VERSION 5.7 ;
  NOWIREEXTENSIONATPIN ON ;
  DIVIDERCHAR "/" ;
  BUSBITCHARS "[]" ;
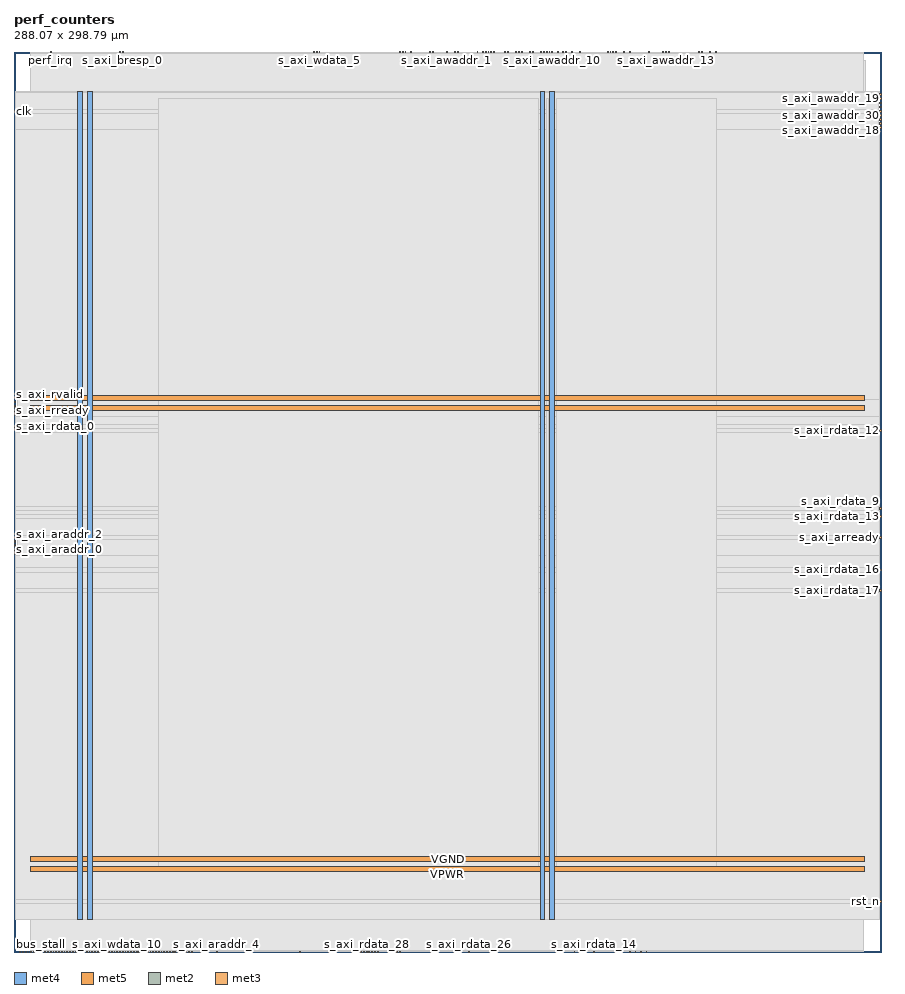
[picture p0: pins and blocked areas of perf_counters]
MACRO perf_counters
  CLASS BLOCK ;
  FOREIGN perf_counters ;
  ORIGIN 0.000 0.000 ;
  SIZE 288.070 BY 298.790 ;
  PIN VGND
    DIRECTION INOUT ;
    USE GROUND ;
    PORT
      LAYER met4 ;
        RECT 24.340 10.640 25.940 285.840 ;
    END
    PORT
      LAYER met4 ;
        RECT 177.940 10.640 179.540 285.840 ;
    END
    PORT
      LAYER met5 ;
        RECT 5.520 30.030 282.440 31.630 ;
    END
    PORT
      LAYER met5 ;
        RECT 5.520 183.210 282.440 184.810 ;
    END
  END VGND
  PIN VPWR
    DIRECTION INOUT ;
    USE POWER ;
    PORT
      LAYER met4 ;
        RECT 21.040 10.640 22.640 285.840 ;
    END
    PORT
      LAYER met4 ;
        RECT 174.640 10.640 176.240 285.840 ;
    END
    PORT
      LAYER met5 ;
        RECT 5.520 26.730 282.440 28.330 ;
    END
    PORT
      LAYER met5 ;
        RECT 5.520 179.910 282.440 181.510 ;
    END
  END VPWR
  PIN accel_busy
    DIRECTION INPUT ;
    USE SIGNAL ;
    PORT
      LAYER met2 ;
        RECT 1.930 0.000 2.210 0.280 ;
    END
  END accel_busy
  PIN bus_stall
    DIRECTION INPUT ;
    USE SIGNAL ;
    PORT
      LAYER met2 ;
        RECT 2.850 0.000 3.130 0.280 ;
    END
  END bus_stall
  PIN cache_hit
    DIRECTION INPUT ;
    USE SIGNAL ;
    PORT
      LAYER met2 ;
        RECT 3.770 0.000 4.050 0.280 ;
    END
  END cache_hit
  PIN cache_miss
    DIRECTION INPUT ;
    USE SIGNAL ;
    PORT
      LAYER met2 ;
        RECT 4.690 0.000 4.970 0.280 ;
    END
  END cache_miss
  PIN clk
    DIRECTION INPUT ;
    USE SIGNAL ;
    ANTENNAGATEAREA 1.286700 ;
    ANTENNADIFFAREA 0.434700 ;
    PORT
      LAYER met3 ;
        RECT 0.000 278.840 0.600 279.440 ;
    END
  END clk
  PIN dma_active
    DIRECTION INPUT ;
    USE SIGNAL ;
    PORT
      LAYER met2 ;
        RECT 5.610 0.000 5.890 0.280 ;
    END
  END dma_active
  PIN dmem_req
    DIRECTION INPUT ;
    USE SIGNAL ;
    PORT
      LAYER met2 ;
        RECT 6.530 0.000 6.810 0.280 ;
    END
  END dmem_req
  PIN dmem_wr
    DIRECTION INPUT ;
    USE SIGNAL ;
    PORT
      LAYER met2 ;
        RECT 7.450 0.000 7.730 0.280 ;
    END
  END dmem_wr
  PIN imem_req
    DIRECTION INPUT ;
    USE SIGNAL ;
    PORT
      LAYER met2 ;
        RECT 8.370 0.000 8.650 0.280 ;
    END
  END imem_req
  PIN irq_taken
    DIRECTION INPUT ;
    USE SIGNAL ;
    PORT
      LAYER met2 ;
        RECT 9.290 0.000 9.570 0.280 ;
    END
  END irq_taken
  PIN perf_irq
    DIRECTION OUTPUT ;
    USE SIGNAL ;
    ANTENNAGATEAREA 0.434700 ;
    ANTENNADIFFAREA 0.434700 ;
    PORT
      LAYER met2 ;
        RECT 12.050 298.510 12.330 298.790 ;
    END
  END perf_irq
  PIN rst_n
    DIRECTION INPUT ;
    USE SIGNAL ;
    ANTENNAGATEAREA 0.647700 ;
    ANTENNADIFFAREA 0.434700 ;
    PORT
      LAYER met3 ;
        RECT 287.470 16.360 288.070 16.960 ;
    END
  END rst_n
  PIN s_axi_araddr_0
    DIRECTION INPUT ;
    USE SIGNAL ;
    ANTENNAGATEAREA 0.647700 ;
    ANTENNADIFFAREA 0.434700 ;
    PORT
      LAYER met3 ;
        RECT 0.000 133.320 0.600 133.920 ;
    END
  END s_axi_araddr_0
  PIN s_axi_araddr_1
    DIRECTION INPUT ;
    USE SIGNAL ;
    ANTENNAGATEAREA 0.647700 ;
    ANTENNADIFFAREA 0.434700 ;
    PORT
      LAYER met3 ;
        RECT 0.000 134.680 0.600 135.280 ;
    END
  END s_axi_araddr_1
  PIN s_axi_araddr_10
    DIRECTION INPUT ;
    USE SIGNAL ;
    PORT
      LAYER met2 ;
        RECT 10.210 0.000 10.490 0.280 ;
    END
  END s_axi_araddr_10
  PIN s_axi_araddr_11
    DIRECTION INPUT ;
    USE SIGNAL ;
    PORT
      LAYER met2 ;
        RECT 11.130 0.000 11.410 0.280 ;
    END
  END s_axi_araddr_11
  PIN s_axi_araddr_12
    DIRECTION INPUT ;
    USE SIGNAL ;
    PORT
      LAYER met2 ;
        RECT 12.050 0.000 12.330 0.280 ;
    END
  END s_axi_araddr_12
  PIN s_axi_araddr_13
    DIRECTION INPUT ;
    USE SIGNAL ;
    PORT
      LAYER met2 ;
        RECT 12.970 0.000 13.250 0.280 ;
    END
  END s_axi_araddr_13
  PIN s_axi_araddr_14
    DIRECTION INPUT ;
    USE SIGNAL ;
    PORT
      LAYER met2 ;
        RECT 13.890 0.000 14.170 0.280 ;
    END
  END s_axi_araddr_14
  PIN s_axi_araddr_15
    DIRECTION INPUT ;
    USE SIGNAL ;
    PORT
      LAYER met2 ;
        RECT 14.810 0.000 15.090 0.280 ;
    END
  END s_axi_araddr_15
  PIN s_axi_araddr_16
    DIRECTION INPUT ;
    USE SIGNAL ;
    PORT
      LAYER met2 ;
        RECT 15.730 0.000 16.010 0.280 ;
    END
  END s_axi_araddr_16
  PIN s_axi_araddr_17
    DIRECTION INPUT ;
    USE SIGNAL ;
    PORT
      LAYER met2 ;
        RECT 16.650 0.000 16.930 0.280 ;
    END
  END s_axi_araddr_17
  PIN s_axi_araddr_18
    DIRECTION INPUT ;
    USE SIGNAL ;
    PORT
      LAYER met2 ;
        RECT 17.570 0.000 17.850 0.280 ;
    END
  END s_axi_araddr_18
  PIN s_axi_araddr_19
    DIRECTION INPUT ;
    USE SIGNAL ;
    PORT
      LAYER met2 ;
        RECT 18.490 0.000 18.770 0.280 ;
    END
  END s_axi_araddr_19
  PIN s_axi_araddr_2
    DIRECTION INPUT ;
    USE SIGNAL ;
    ANTENNAGATEAREA 0.647700 ;
    ANTENNADIFFAREA 0.434700 ;
    PORT
      LAYER met3 ;
        RECT 0.000 136.040 0.600 136.640 ;
    END
  END s_axi_araddr_2
  PIN s_axi_araddr_20
    DIRECTION INPUT ;
    USE SIGNAL ;
    PORT
      LAYER met2 ;
        RECT 19.410 0.000 19.690 0.280 ;
    END
  END s_axi_araddr_20
  PIN s_axi_araddr_21
    DIRECTION INPUT ;
    USE SIGNAL ;
    PORT
      LAYER met2 ;
        RECT 20.330 0.000 20.610 0.280 ;
    END
  END s_axi_araddr_21
  PIN s_axi_araddr_22
    DIRECTION INPUT ;
    USE SIGNAL ;
    PORT
      LAYER met2 ;
        RECT 21.250 0.000 21.530 0.280 ;
    END
  END s_axi_araddr_22
  PIN s_axi_araddr_23
    DIRECTION INPUT ;
    USE SIGNAL ;
    PORT
      LAYER met2 ;
        RECT 22.170 0.000 22.450 0.280 ;
    END
  END s_axi_araddr_23
  PIN s_axi_araddr_24
    DIRECTION INPUT ;
    USE SIGNAL ;
    PORT
      LAYER met2 ;
        RECT 23.090 0.000 23.370 0.280 ;
    END
  END s_axi_araddr_24
  PIN s_axi_araddr_25
    DIRECTION INPUT ;
    USE SIGNAL ;
    PORT
      LAYER met2 ;
        RECT 24.010 0.000 24.290 0.280 ;
    END
  END s_axi_araddr_25
  PIN s_axi_araddr_26
    DIRECTION INPUT ;
    USE SIGNAL ;
    PORT
      LAYER met2 ;
        RECT 24.930 0.000 25.210 0.280 ;
    END
  END s_axi_araddr_26
  PIN s_axi_araddr_27
    DIRECTION INPUT ;
    USE SIGNAL ;
    PORT
      LAYER met2 ;
        RECT 25.850 0.000 26.130 0.280 ;
    END
  END s_axi_araddr_27
  PIN s_axi_araddr_28
    DIRECTION INPUT ;
    USE SIGNAL ;
    PORT
      LAYER met2 ;
        RECT 26.770 0.000 27.050 0.280 ;
    END
  END s_axi_araddr_28
  PIN s_axi_araddr_29
    DIRECTION INPUT ;
    USE SIGNAL ;
    PORT
      LAYER met2 ;
        RECT 27.690 0.000 27.970 0.280 ;
    END
  END s_axi_araddr_29
  PIN s_axi_araddr_3
    DIRECTION INPUT ;
    USE SIGNAL ;
    ANTENNAGATEAREA 0.647700 ;
    ANTENNADIFFAREA 0.434700 ;
    PORT
      LAYER met3 ;
        RECT 0.000 131.960 0.600 132.560 ;
    END
  END s_axi_araddr_3
  PIN s_axi_araddr_30
    DIRECTION INPUT ;
    USE SIGNAL ;
    PORT
      LAYER met2 ;
        RECT 28.610 0.000 28.890 0.280 ;
    END
  END s_axi_araddr_30
  PIN s_axi_araddr_31
    DIRECTION INPUT ;
    USE SIGNAL ;
    PORT
      LAYER met2 ;
        RECT 29.530 0.000 29.810 0.280 ;
    END
  END s_axi_araddr_31
  PIN s_axi_araddr_4
    DIRECTION INPUT ;
    USE SIGNAL ;
    ANTENNAGATEAREA 0.631200 ;
    ANTENNADIFFAREA 0.434700 ;
    PORT
      LAYER met2 ;
        RECT 67.250 0.000 67.530 0.280 ;
    END
  END s_axi_araddr_4
  PIN s_axi_araddr_5
    DIRECTION INPUT ;
    USE SIGNAL ;
    PORT
      LAYER met2 ;
        RECT 30.450 0.000 30.730 0.280 ;
    END
  END s_axi_araddr_5
  PIN s_axi_araddr_6
    DIRECTION INPUT ;
    USE SIGNAL ;
    PORT
      LAYER met2 ;
        RECT 31.370 0.000 31.650 0.280 ;
    END
  END s_axi_araddr_6
  PIN s_axi_araddr_7
    DIRECTION INPUT ;
    USE SIGNAL ;
    ANTENNAGATEAREA 0.647700 ;
    ANTENNADIFFAREA 0.434700 ;
    PORT
      LAYER met2 ;
        RECT 94.850 0.000 95.130 0.280 ;
    END
  END s_axi_araddr_7
  PIN s_axi_araddr_8
    DIRECTION INPUT ;
    USE SIGNAL ;
    PORT
      LAYER met2 ;
        RECT 32.290 0.000 32.570 0.280 ;
    END
  END s_axi_araddr_8
  PIN s_axi_araddr_9
    DIRECTION INPUT ;
    USE SIGNAL ;
    PORT
      LAYER met2 ;
        RECT 33.210 0.000 33.490 0.280 ;
    END
  END s_axi_araddr_9
  PIN s_axi_arready
    DIRECTION OUTPUT ;
    USE SIGNAL ;
    ANTENNAGATEAREA 0.434700 ;
    ANTENNADIFFAREA 1.137600 ;
    PORT
      LAYER met3 ;
        RECT 287.470 137.400 288.070 138.000 ;
    END
  END s_axi_arready
  PIN s_axi_arvalid
    DIRECTION INPUT ;
    USE SIGNAL ;
    ANTENNAGATEAREA 0.647700 ;
    ANTENNADIFFAREA 0.434700 ;
    PORT
      LAYER met3 ;
        RECT 0.000 180.920 0.600 181.520 ;
    END
  END s_axi_arvalid
  PIN s_axi_awaddr_0
    DIRECTION INPUT ;
    USE SIGNAL ;
    ANTENNAGATEAREA 0.647700 ;
    ANTENNADIFFAREA 0.434700 ;
    PORT
      LAYER met2 ;
        RECT 129.810 298.510 130.090 298.790 ;
    END
  END s_axi_awaddr_0
  PIN s_axi_awaddr_1
    DIRECTION INPUT ;
    USE SIGNAL ;
    ANTENNAGATEAREA 0.647700 ;
    ANTENNADIFFAREA 0.434700 ;
    PORT
      LAYER met2 ;
        RECT 143.610 298.510 143.890 298.790 ;
    END
  END s_axi_awaddr_1
  PIN s_axi_awaddr_10
    DIRECTION INPUT ;
    USE SIGNAL ;
    ANTENNAGATEAREA 0.647700 ;
    ANTENNADIFFAREA 0.434700 ;
    PORT
      LAYER met2 ;
        RECT 178.570 298.510 178.850 298.790 ;
    END
  END s_axi_awaddr_10
  PIN s_axi_awaddr_11
    DIRECTION INPUT ;
    USE SIGNAL ;
    ANTENNAGATEAREA 0.647700 ;
    ANTENNADIFFAREA 0.434700 ;
    PORT
      LAYER met2 ;
        RECT 187.770 298.510 188.050 298.790 ;
    END
  END s_axi_awaddr_11
  PIN s_axi_awaddr_12
    DIRECTION INPUT ;
    USE SIGNAL ;
    ANTENNAGATEAREA 0.647700 ;
    ANTENNADIFFAREA 0.434700 ;
    PORT
      LAYER met3 ;
        RECT 287.470 284.280 288.070 284.880 ;
    END
  END s_axi_awaddr_12
  PIN s_axi_awaddr_13
    DIRECTION INPUT ;
    USE SIGNAL ;
    ANTENNAGATEAREA 0.647700 ;
    ANTENNADIFFAREA 0.434700 ;
    PORT
      LAYER met2 ;
        RECT 216.290 298.510 216.570 298.790 ;
    END
  END s_axi_awaddr_13
  PIN s_axi_awaddr_14
    DIRECTION INPUT ;
    USE SIGNAL ;
    ANTENNAGATEAREA 0.647700 ;
    ANTENNADIFFAREA 0.434700 ;
    PORT
      LAYER met2 ;
        RECT 210.770 298.510 211.050 298.790 ;
    END
  END s_axi_awaddr_14
  PIN s_axi_awaddr_15
    DIRECTION INPUT ;
    USE SIGNAL ;
    ANTENNAGATEAREA 0.647700 ;
    ANTENNADIFFAREA 0.434700 ;
    PORT
      LAYER met3 ;
        RECT 287.470 278.840 288.070 279.440 ;
    END
  END s_axi_awaddr_15
  PIN s_axi_awaddr_16
    DIRECTION INPUT ;
    USE SIGNAL ;
    ANTENNAGATEAREA 0.647700 ;
    ANTENNADIFFAREA 0.434700 ;
    PORT
      LAYER met2 ;
        RECT 227.330 298.510 227.610 298.790 ;
    END
  END s_axi_awaddr_16
  PIN s_axi_awaddr_17
    DIRECTION INPUT ;
    USE SIGNAL ;
    ANTENNAGATEAREA 0.647700 ;
    ANTENNADIFFAREA 0.434700 ;
    PORT
      LAYER met2 ;
        RECT 202.490 298.510 202.770 298.790 ;
    END
  END s_axi_awaddr_17
  PIN s_axi_awaddr_18
    DIRECTION INPUT ;
    USE SIGNAL ;
    ANTENNAGATEAREA 0.647700 ;
    ANTENNADIFFAREA 0.434700 ;
    PORT
      LAYER met3 ;
        RECT 287.470 274.760 288.070 275.360 ;
    END
  END s_axi_awaddr_18
  PIN s_axi_awaddr_19
    DIRECTION INPUT ;
    USE SIGNAL ;
    ANTENNAGATEAREA 0.647700 ;
    ANTENNADIFFAREA 0.434700 ;
    PORT
      LAYER met3 ;
        RECT 287.470 282.920 288.070 283.520 ;
    END
  END s_axi_awaddr_19
  PIN s_axi_awaddr_2
    DIRECTION INPUT ;
    USE SIGNAL ;
    ANTENNAGATEAREA 0.647700 ;
    ANTENNADIFFAREA 0.434700 ;
    PORT
      LAYER met2 ;
        RECT 147.290 298.510 147.570 298.790 ;
    END
  END s_axi_awaddr_2
  PIN s_axi_awaddr_20
    DIRECTION INPUT ;
    USE SIGNAL ;
    ANTENNAGATEAREA 0.647700 ;
    ANTENNADIFFAREA 0.434700 ;
    PORT
      LAYER met3 ;
        RECT 287.470 276.120 288.070 276.720 ;
    END
  END s_axi_awaddr_20
  PIN s_axi_awaddr_21
    DIRECTION INPUT ;
    USE SIGNAL ;
    ANTENNAGATEAREA 0.647700 ;
    ANTENNADIFFAREA 0.434700 ;
    PORT
      LAYER met2 ;
        RECT 231.010 298.510 231.290 298.790 ;
    END
  END s_axi_awaddr_21
  PIN s_axi_awaddr_22
    DIRECTION INPUT ;
    USE SIGNAL ;
    ANTENNAGATEAREA 0.647700 ;
    ANTENNADIFFAREA 0.434700 ;
    PORT
      LAYER met3 ;
        RECT 287.470 281.560 288.070 282.160 ;
    END
  END s_axi_awaddr_22
  PIN s_axi_awaddr_23
    DIRECTION INPUT ;
    USE SIGNAL ;
    ANTENNAGATEAREA 0.647700 ;
    ANTENNADIFFAREA 0.434700 ;
    PORT
      LAYER met3 ;
        RECT 287.470 280.200 288.070 280.800 ;
    END
  END s_axi_awaddr_23
  PIN s_axi_awaddr_24
    DIRECTION INPUT ;
    USE SIGNAL ;
    ANTENNAGATEAREA 0.647700 ;
    ANTENNADIFFAREA 0.434700 ;
    PORT
      LAYER met2 ;
        RECT 232.850 298.510 233.130 298.790 ;
    END
  END s_axi_awaddr_24
  PIN s_axi_awaddr_25
    DIRECTION INPUT ;
    USE SIGNAL ;
    ANTENNAGATEAREA 0.647700 ;
    ANTENNADIFFAREA 0.434700 ;
    PORT
      LAYER met2 ;
        RECT 215.370 298.510 215.650 298.790 ;
    END
  END s_axi_awaddr_25
  PIN s_axi_awaddr_26
    DIRECTION INPUT ;
    USE SIGNAL ;
    ANTENNAGATEAREA 0.647700 ;
    ANTENNADIFFAREA 0.434700 ;
    PORT
      LAYER met2 ;
        RECT 196.970 298.510 197.250 298.790 ;
    END
  END s_axi_awaddr_26
  PIN s_axi_awaddr_27
    DIRECTION INPUT ;
    USE SIGNAL ;
    ANTENNAGATEAREA 0.647700 ;
    ANTENNADIFFAREA 0.434700 ;
    PORT
      LAYER met2 ;
        RECT 197.890 298.510 198.170 298.790 ;
    END
  END s_axi_awaddr_27
  PIN s_axi_awaddr_28
    DIRECTION INPUT ;
    USE SIGNAL ;
    ANTENNAGATEAREA 0.647700 ;
    ANTENNADIFFAREA 0.434700 ;
    PORT
      LAYER met2 ;
        RECT 217.210 298.510 217.490 298.790 ;
    END
  END s_axi_awaddr_28
  PIN s_axi_awaddr_29
    DIRECTION INPUT ;
    USE SIGNAL ;
    ANTENNAGATEAREA 0.647700 ;
    ANTENNADIFFAREA 0.434700 ;
    PORT
      LAYER met2 ;
        RECT 228.250 298.510 228.530 298.790 ;
    END
  END s_axi_awaddr_29
  PIN s_axi_awaddr_3
    DIRECTION INPUT ;
    USE SIGNAL ;
    ANTENNAGATEAREA 0.647700 ;
    ANTENNADIFFAREA 0.434700 ;
    PORT
      LAYER met2 ;
        RECT 159.250 298.510 159.530 298.790 ;
    END
  END s_axi_awaddr_3
  PIN s_axi_awaddr_30
    DIRECTION INPUT ;
    USE SIGNAL ;
    ANTENNAGATEAREA 0.647700 ;
    ANTENNADIFFAREA 0.434700 ;
    PORT
      LAYER met3 ;
        RECT 287.470 277.480 288.070 278.080 ;
    END
  END s_axi_awaddr_30
  PIN s_axi_awaddr_31
    DIRECTION INPUT ;
    USE SIGNAL ;
    ANTENNAGATEAREA 0.647700 ;
    ANTENNADIFFAREA 0.434700 ;
    PORT
      LAYER met3 ;
        RECT 287.470 273.400 288.070 274.000 ;
    END
  END s_axi_awaddr_31
  PIN s_axi_awaddr_4
    DIRECTION INPUT ;
    USE SIGNAL ;
    ANTENNAGATEAREA 0.647700 ;
    ANTENNADIFFAREA 0.434700 ;
    PORT
      LAYER met2 ;
        RECT 139.010 298.510 139.290 298.790 ;
    END
  END s_axi_awaddr_4
  PIN s_axi_awaddr_5
    DIRECTION INPUT ;
    USE SIGNAL ;
    ANTENNAGATEAREA 0.647700 ;
    ANTENNADIFFAREA 0.434700 ;
    PORT
      LAYER met2 ;
        RECT 157.410 298.510 157.690 298.790 ;
    END
  END s_axi_awaddr_5
  PIN s_axi_awaddr_6
    DIRECTION INPUT ;
    USE SIGNAL ;
    ANTENNAGATEAREA 0.647700 ;
    ANTENNADIFFAREA 0.434700 ;
    PORT
      LAYER met2 ;
        RECT 127.970 298.510 128.250 298.790 ;
    END
  END s_axi_awaddr_6
  PIN s_axi_awaddr_7
    DIRECTION INPUT ;
    USE SIGNAL ;
    ANTENNAGATEAREA 0.647700 ;
    ANTENNADIFFAREA 0.434700 ;
    PORT
      LAYER met2 ;
        RECT 128.890 298.510 129.170 298.790 ;
    END
  END s_axi_awaddr_7
  PIN s_axi_awaddr_8
    DIRECTION INPUT ;
    USE SIGNAL ;
    ANTENNAGATEAREA 0.647700 ;
    ANTENNADIFFAREA 0.434700 ;
    PORT
      LAYER met2 ;
        RECT 185.010 298.510 185.290 298.790 ;
    END
  END s_axi_awaddr_8
  PIN s_axi_awaddr_9
    DIRECTION INPUT ;
    USE SIGNAL ;
    ANTENNAGATEAREA 0.647700 ;
    ANTENNADIFFAREA 0.434700 ;
    PORT
      LAYER met2 ;
        RECT 182.250 298.510 182.530 298.790 ;
    END
  END s_axi_awaddr_9
  PIN s_axi_awready
    DIRECTION OUTPUT ;
    USE SIGNAL ;
    ANTENNAGATEAREA 0.434700 ;
    ANTENNADIFFAREA 1.137600 ;
    PORT
      LAYER met2 ;
        RECT 183.170 298.510 183.450 298.790 ;
    END
  END s_axi_awready
  PIN s_axi_awvalid
    DIRECTION INPUT ;
    USE SIGNAL ;
    ANTENNAGATEAREA 0.647700 ;
    ANTENNADIFFAREA 0.434700 ;
    PORT
      LAYER met2 ;
        RECT 172.130 298.510 172.410 298.790 ;
    END
  END s_axi_awvalid
  PIN s_axi_bready
    DIRECTION INPUT ;
    USE SIGNAL ;
    ANTENNAGATEAREA 0.647700 ;
    ANTENNADIFFAREA 0.434700 ;
    PORT
      LAYER met2 ;
        RECT 162.930 298.510 163.210 298.790 ;
    END
  END s_axi_bready
  PIN s_axi_bresp_0
    DIRECTION OUTPUT ;
    USE SIGNAL ;
    ANTENNAGATEAREA 0.434700 ;
    ANTENNADIFFAREA 1.137600 ;
    PORT
      LAYER met2 ;
        RECT 35.970 298.510 36.250 298.790 ;
    END
  END s_axi_bresp_0
  PIN s_axi_bresp_1
    DIRECTION OUTPUT ;
    USE SIGNAL ;
    ANTENNAGATEAREA 0.434700 ;
    ANTENNADIFFAREA 1.137600 ;
    PORT
      LAYER met2 ;
        RECT 35.050 298.510 35.330 298.790 ;
    END
  END s_axi_bresp_1
  PIN s_axi_bvalid
    DIRECTION OUTPUT ;
    USE SIGNAL ;
    ANTENNAGATEAREA 0.434700 ;
    ANTENNADIFFAREA 1.137600 ;
    PORT
      LAYER met2 ;
        RECT 166.610 298.510 166.890 298.790 ;
    END
  END s_axi_bvalid
  PIN s_axi_rdata_0
    DIRECTION OUTPUT ;
    USE SIGNAL ;
    ANTENNAGATEAREA 0.434700 ;
    ANTENNADIFFAREA 1.137600 ;
    PORT
      LAYER met3 ;
        RECT 0.000 174.120 0.600 174.720 ;
    END
  END s_axi_rdata_0
  PIN s_axi_rdata_1
    DIRECTION OUTPUT ;
    USE SIGNAL ;
    ANTENNAGATEAREA 0.434700 ;
    ANTENNADIFFAREA 1.137600 ;
    PORT
      LAYER met2 ;
        RECT 171.210 298.510 171.490 298.790 ;
    END
  END s_axi_rdata_1
  PIN s_axi_rdata_10
    DIRECTION OUTPUT ;
    USE SIGNAL ;
    ANTENNAGATEAREA 0.434700 ;
    ANTENNADIFFAREA 1.137600 ;
    PORT
      LAYER met2 ;
        RECT 204.330 298.510 204.610 298.790 ;
    END
  END s_axi_rdata_10
  PIN s_axi_rdata_11
    DIRECTION OUTPUT ;
    USE SIGNAL ;
    ANTENNAGATEAREA 0.434700 ;
    ANTENNADIFFAREA 1.137600 ;
    PORT
      LAYER met2 ;
        RECT 198.810 298.510 199.090 298.790 ;
    END
  END s_axi_rdata_11
  PIN s_axi_rdata_12
    DIRECTION OUTPUT ;
    USE SIGNAL ;
    ANTENNAGATEAREA 0.434700 ;
    ANTENNADIFFAREA 1.137600 ;
    PORT
      LAYER met3 ;
        RECT 287.470 172.760 288.070 173.360 ;
    END
  END s_axi_rdata_12
  PIN s_axi_rdata_13
    DIRECTION OUTPUT ;
    USE SIGNAL ;
    ANTENNAGATEAREA 0.434700 ;
    ANTENNADIFFAREA 1.137600 ;
    PORT
      LAYER met3 ;
        RECT 287.470 144.200 288.070 144.800 ;
    END
  END s_axi_rdata_13
  PIN s_axi_rdata_14
    DIRECTION OUTPUT ;
    USE SIGNAL ;
    ANTENNAGATEAREA 0.434700 ;
    ANTENNADIFFAREA 1.137600 ;
    PORT
      LAYER met2 ;
        RECT 192.370 0.000 192.650 0.280 ;
    END
  END s_axi_rdata_14
  PIN s_axi_rdata_15
    DIRECTION OUTPUT ;
    USE SIGNAL ;
    ANTENNAGATEAREA 0.434700 ;
    ANTENNADIFFAREA 1.137600 ;
    PORT
      LAYER met2 ;
        RECT 206.170 0.000 206.450 0.280 ;
    END
  END s_axi_rdata_15
  PIN s_axi_rdata_16
    DIRECTION OUTPUT ;
    USE SIGNAL ;
    ANTENNAGATEAREA 0.434700 ;
    ANTENNADIFFAREA 1.137600 ;
    PORT
      LAYER met3 ;
        RECT 287.470 126.520 288.070 127.120 ;
    END
  END s_axi_rdata_16
  PIN s_axi_rdata_17
    DIRECTION OUTPUT ;
    USE SIGNAL ;
    ANTENNAGATEAREA 0.434700 ;
    ANTENNADIFFAREA 1.137600 ;
    PORT
      LAYER met3 ;
        RECT 287.470 119.720 288.070 120.320 ;
    END
  END s_axi_rdata_17
  PIN s_axi_rdata_18
    DIRECTION OUTPUT ;
    USE SIGNAL ;
    ANTENNAGATEAREA 0.434700 ;
    ANTENNADIFFAREA 1.137600 ;
    PORT
      LAYER met2 ;
        RECT 209.850 0.000 210.130 0.280 ;
    END
  END s_axi_rdata_18
  PIN s_axi_rdata_19
    DIRECTION OUTPUT ;
    USE SIGNAL ;
    ANTENNAGATEAREA 0.434700 ;
    ANTENNADIFFAREA 1.137600 ;
    PORT
      LAYER met2 ;
        RECT 208.010 0.000 208.290 0.280 ;
    END
  END s_axi_rdata_19
  PIN s_axi_rdata_2
    DIRECTION OUTPUT ;
    USE SIGNAL ;
    ANTENNAGATEAREA 0.434700 ;
    ANTENNADIFFAREA 1.137600 ;
    PORT
      LAYER met3 ;
        RECT 0.000 178.200 0.600 178.800 ;
    END
  END s_axi_rdata_2
  PIN s_axi_rdata_20
    DIRECTION OUTPUT ;
    USE SIGNAL ;
    ANTENNAGATEAREA 0.434700 ;
    ANTENNADIFFAREA 1.137600 ;
    PORT
      LAYER met2 ;
        RECT 204.330 0.000 204.610 0.280 ;
    END
  END s_axi_rdata_20
  PIN s_axi_rdata_21
    DIRECTION OUTPUT ;
    USE SIGNAL ;
    ANTENNAGATEAREA 0.434700 ;
    ANTENNADIFFAREA 1.137600 ;
    PORT
      LAYER met2 ;
        RECT 185.930 0.000 186.210 0.280 ;
    END
  END s_axi_rdata_21
  PIN s_axi_rdata_22
    DIRECTION OUTPUT ;
    USE SIGNAL ;
    ANTENNAGATEAREA 0.434700 ;
    ANTENNADIFFAREA 1.137600 ;
    PORT
      LAYER met2 ;
        RECT 127.050 0.000 127.330 0.280 ;
    END
  END s_axi_rdata_22
  PIN s_axi_rdata_23
    DIRECTION OUTPUT ;
    USE SIGNAL ;
    ANTENNAGATEAREA 0.434700 ;
    ANTENNADIFFAREA 1.137600 ;
    PORT
      LAYER met2 ;
        RECT 119.690 0.000 119.970 0.280 ;
    END
  END s_axi_rdata_23
  PIN s_axi_rdata_24
    DIRECTION OUTPUT ;
    USE SIGNAL ;
    ANTENNAGATEAREA 0.434700 ;
    ANTENNADIFFAREA 1.137600 ;
    PORT
      LAYER met2 ;
        RECT 127.970 0.000 128.250 0.280 ;
    END
  END s_axi_rdata_24
  PIN s_axi_rdata_25
    DIRECTION OUTPUT ;
    USE SIGNAL ;
    ANTENNAGATEAREA 0.434700 ;
    ANTENNADIFFAREA 1.137600 ;
    PORT
      LAYER met2 ;
        RECT 115.090 0.000 115.370 0.280 ;
    END
  END s_axi_rdata_25
  PIN s_axi_rdata_26
    DIRECTION OUTPUT ;
    USE SIGNAL ;
    ANTENNAGATEAREA 0.434700 ;
    ANTENNADIFFAREA 1.137600 ;
    PORT
      LAYER met2 ;
        RECT 150.970 0.000 151.250 0.280 ;
    END
  END s_axi_rdata_26
  PIN s_axi_rdata_27
    DIRECTION OUTPUT ;
    USE SIGNAL ;
    ANTENNAGATEAREA 0.434700 ;
    ANTENNADIFFAREA 1.137600 ;
    PORT
      LAYER met2 ;
        RECT 116.010 0.000 116.290 0.280 ;
    END
  END s_axi_rdata_27
  PIN s_axi_rdata_28
    DIRECTION OUTPUT ;
    USE SIGNAL ;
    ANTENNAGATEAREA 0.434700 ;
    ANTENNADIFFAREA 1.137600 ;
    PORT
      LAYER met2 ;
        RECT 116.930 0.000 117.210 0.280 ;
    END
  END s_axi_rdata_28
  PIN s_axi_rdata_29
    DIRECTION OUTPUT ;
    USE SIGNAL ;
    ANTENNAGATEAREA 0.434700 ;
    ANTENNADIFFAREA 1.137600 ;
    PORT
      LAYER met2 ;
        RECT 117.850 0.000 118.130 0.280 ;
    END
  END s_axi_rdata_29
  PIN s_axi_rdata_3
    DIRECTION OUTPUT ;
    USE SIGNAL ;
    ANTENNAGATEAREA 0.434700 ;
    ANTENNADIFFAREA 1.137600 ;
    PORT
      LAYER met2 ;
        RECT 131.650 298.510 131.930 298.790 ;
    END
  END s_axi_rdata_3
  PIN s_axi_rdata_30
    DIRECTION OUTPUT ;
    USE SIGNAL ;
    ANTENNAGATEAREA 0.434700 ;
    ANTENNADIFFAREA 1.137600 ;
    PORT
      LAYER met2 ;
        RECT 118.770 0.000 119.050 0.280 ;
    END
  END s_axi_rdata_30
  PIN s_axi_rdata_31
    DIRECTION OUTPUT ;
    USE SIGNAL ;
    ANTENNAGATEAREA 0.434700 ;
    ANTENNADIFFAREA 1.137600 ;
    PORT
      LAYER met2 ;
        RECT 120.610 0.000 120.890 0.280 ;
    END
  END s_axi_rdata_31
  PIN s_axi_rdata_4
    DIRECTION OUTPUT ;
    USE SIGNAL ;
    ANTENNAGATEAREA 0.434700 ;
    ANTENNADIFFAREA 1.137600 ;
    PORT
      LAYER met2 ;
        RECT 168.450 298.510 168.730 298.790 ;
    END
  END s_axi_rdata_4
  PIN s_axi_rdata_5
    DIRECTION OUTPUT ;
    USE SIGNAL ;
    ANTENNAGATEAREA 0.434700 ;
    ANTENNADIFFAREA 1.137600 ;
    PORT
      LAYER met2 ;
        RECT 163.850 298.510 164.130 298.790 ;
    END
  END s_axi_rdata_5
  PIN s_axi_rdata_6
    DIRECTION OUTPUT ;
    USE SIGNAL ;
    ANTENNAGATEAREA 0.434700 ;
    ANTENNADIFFAREA 1.137600 ;
    PORT
      LAYER met2 ;
        RECT 180.410 298.510 180.690 298.790 ;
    END
  END s_axi_rdata_6
  PIN s_axi_rdata_7
    DIRECTION OUTPUT ;
    USE SIGNAL ;
    ANTENNAGATEAREA 0.434700 ;
    ANTENNADIFFAREA 1.137600 ;
    PORT
      LAYER met2 ;
        RECT 177.650 298.510 177.930 298.790 ;
    END
  END s_axi_rdata_7
  PIN s_axi_rdata_8
    DIRECTION OUTPUT ;
    USE SIGNAL ;
    ANTENNAGATEAREA 0.434700 ;
    ANTENNADIFFAREA 1.137600 ;
    PORT
      LAYER met2 ;
        RECT 199.730 298.510 200.010 298.790 ;
    END
  END s_axi_rdata_8
  PIN s_axi_rdata_9
    DIRECTION OUTPUT ;
    USE SIGNAL ;
    ANTENNAGATEAREA 0.434700 ;
    ANTENNADIFFAREA 1.137600 ;
    PORT
      LAYER met3 ;
        RECT 287.470 146.920 288.070 147.520 ;
    END
  END s_axi_rdata_9
  PIN s_axi_rready
    DIRECTION INPUT ;
    USE SIGNAL ;
    ANTENNAGATEAREA 0.647700 ;
    ANTENNADIFFAREA 0.434700 ;
    PORT
      LAYER met3 ;
        RECT 0.000 179.560 0.600 180.160 ;
    END
  END s_axi_rready
  PIN s_axi_rresp_0
    DIRECTION OUTPUT ;
    USE SIGNAL ;
    ANTENNAGATEAREA 0.434700 ;
    ANTENNADIFFAREA 1.137600 ;
    PORT
      LAYER met2 ;
        RECT 175.810 298.510 176.090 298.790 ;
    END
  END s_axi_rresp_0
  PIN s_axi_rresp_1
    DIRECTION OUTPUT ;
    USE SIGNAL ;
    ANTENNAGATEAREA 0.434700 ;
    ANTENNADIFFAREA 1.137600 ;
    PORT
      LAYER met2 ;
        RECT 174.890 298.510 175.170 298.790 ;
    END
  END s_axi_rresp_1
  PIN s_axi_rvalid
    DIRECTION OUTPUT ;
    USE SIGNAL ;
    ANTENNAGATEAREA 0.434700 ;
    ANTENNADIFFAREA 1.137600 ;
    PORT
      LAYER met3 ;
        RECT 0.000 182.280 0.600 182.880 ;
    END
  END s_axi_rvalid
  PIN s_axi_wdata_0
    DIRECTION INPUT ;
    USE SIGNAL ;
    ANTENNAGATEAREA 0.647700 ;
    ANTENNADIFFAREA 0.434700 ;
    PORT
      LAYER met2 ;
        RECT 155.570 298.510 155.850 298.790 ;
    END
  END s_axi_wdata_0
  PIN s_axi_wdata_1
    DIRECTION INPUT ;
    USE SIGNAL ;
    ANTENNAGATEAREA 0.647700 ;
    ANTENNADIFFAREA 0.434700 ;
    PORT
      LAYER met2 ;
        RECT 158.330 298.510 158.610 298.790 ;
    END
  END s_axi_wdata_1
  PIN s_axi_wdata_10
    DIRECTION INPUT ;
    USE SIGNAL ;
    PORT
      LAYER met2 ;
        RECT 34.130 0.000 34.410 0.280 ;
    END
  END s_axi_wdata_10
  PIN s_axi_wdata_11
    DIRECTION INPUT ;
    USE SIGNAL ;
    PORT
      LAYER met2 ;
        RECT 35.050 0.000 35.330 0.280 ;
    END
  END s_axi_wdata_11
  PIN s_axi_wdata_12
    DIRECTION INPUT ;
    USE SIGNAL ;
    PORT
      LAYER met2 ;
        RECT 35.970 0.000 36.250 0.280 ;
    END
  END s_axi_wdata_12
  PIN s_axi_wdata_13
    DIRECTION INPUT ;
    USE SIGNAL ;
    PORT
      LAYER met2 ;
        RECT 36.890 0.000 37.170 0.280 ;
    END
  END s_axi_wdata_13
  PIN s_axi_wdata_14
    DIRECTION INPUT ;
    USE SIGNAL ;
    PORT
      LAYER met2 ;
        RECT 37.810 0.000 38.090 0.280 ;
    END
  END s_axi_wdata_14
  PIN s_axi_wdata_15
    DIRECTION INPUT ;
    USE SIGNAL ;
    PORT
      LAYER met2 ;
        RECT 38.730 0.000 39.010 0.280 ;
    END
  END s_axi_wdata_15
  PIN s_axi_wdata_16
    DIRECTION INPUT ;
    USE SIGNAL ;
    PORT
      LAYER met2 ;
        RECT 39.650 0.000 39.930 0.280 ;
    END
  END s_axi_wdata_16
  PIN s_axi_wdata_17
    DIRECTION INPUT ;
    USE SIGNAL ;
    PORT
      LAYER met2 ;
        RECT 40.570 0.000 40.850 0.280 ;
    END
  END s_axi_wdata_17
  PIN s_axi_wdata_18
    DIRECTION INPUT ;
    USE SIGNAL ;
    PORT
      LAYER met2 ;
        RECT 41.490 0.000 41.770 0.280 ;
    END
  END s_axi_wdata_18
  PIN s_axi_wdata_19
    DIRECTION INPUT ;
    USE SIGNAL ;
    PORT
      LAYER met2 ;
        RECT 42.410 0.000 42.690 0.280 ;
    END
  END s_axi_wdata_19
  PIN s_axi_wdata_2
    DIRECTION INPUT ;
    USE SIGNAL ;
    ANTENNAGATEAREA 0.647700 ;
    ANTENNADIFFAREA 0.434700 ;
    PORT
      LAYER met2 ;
        RECT 153.730 298.510 154.010 298.790 ;
    END
  END s_axi_wdata_2
  PIN s_axi_wdata_20
    DIRECTION INPUT ;
    USE SIGNAL ;
    PORT
      LAYER met2 ;
        RECT 43.330 0.000 43.610 0.280 ;
    END
  END s_axi_wdata_20
  PIN s_axi_wdata_21
    DIRECTION INPUT ;
    USE SIGNAL ;
    PORT
      LAYER met2 ;
        RECT 44.250 0.000 44.530 0.280 ;
    END
  END s_axi_wdata_21
  PIN s_axi_wdata_22
    DIRECTION INPUT ;
    USE SIGNAL ;
    PORT
      LAYER met2 ;
        RECT 45.170 0.000 45.450 0.280 ;
    END
  END s_axi_wdata_22
  PIN s_axi_wdata_23
    DIRECTION INPUT ;
    USE SIGNAL ;
    PORT
      LAYER met2 ;
        RECT 46.090 0.000 46.370 0.280 ;
    END
  END s_axi_wdata_23
  PIN s_axi_wdata_24
    DIRECTION INPUT ;
    USE SIGNAL ;
    PORT
      LAYER met2 ;
        RECT 47.010 0.000 47.290 0.280 ;
    END
  END s_axi_wdata_24
  PIN s_axi_wdata_25
    DIRECTION INPUT ;
    USE SIGNAL ;
    PORT
      LAYER met2 ;
        RECT 47.930 0.000 48.210 0.280 ;
    END
  END s_axi_wdata_25
  PIN s_axi_wdata_26
    DIRECTION INPUT ;
    USE SIGNAL ;
    PORT
      LAYER met2 ;
        RECT 48.850 0.000 49.130 0.280 ;
    END
  END s_axi_wdata_26
  PIN s_axi_wdata_27
    DIRECTION INPUT ;
    USE SIGNAL ;
    PORT
      LAYER met2 ;
        RECT 49.770 0.000 50.050 0.280 ;
    END
  END s_axi_wdata_27
  PIN s_axi_wdata_28
    DIRECTION INPUT ;
    USE SIGNAL ;
    PORT
      LAYER met2 ;
        RECT 50.690 0.000 50.970 0.280 ;
    END
  END s_axi_wdata_28
  PIN s_axi_wdata_29
    DIRECTION INPUT ;
    USE SIGNAL ;
    PORT
      LAYER met2 ;
        RECT 51.610 0.000 51.890 0.280 ;
    END
  END s_axi_wdata_29
  PIN s_axi_wdata_3
    DIRECTION INPUT ;
    USE SIGNAL ;
    ANTENNAGATEAREA 0.647700 ;
    ANTENNADIFFAREA 0.434700 ;
    PORT
      LAYER met2 ;
        RECT 99.450 298.510 99.730 298.790 ;
    END
  END s_axi_wdata_3
  PIN s_axi_wdata_30
    DIRECTION INPUT ;
    USE SIGNAL ;
    PORT
      LAYER met2 ;
        RECT 52.530 0.000 52.810 0.280 ;
    END
  END s_axi_wdata_30
  PIN s_axi_wdata_31
    DIRECTION INPUT ;
    USE SIGNAL ;
    PORT
      LAYER met2 ;
        RECT 53.450 0.000 53.730 0.280 ;
    END
  END s_axi_wdata_31
  PIN s_axi_wdata_4
    DIRECTION INPUT ;
    USE SIGNAL ;
    ANTENNAGATEAREA 0.647700 ;
    ANTENNADIFFAREA 0.434700 ;
    PORT
      LAYER met2 ;
        RECT 100.370 298.510 100.650 298.790 ;
    END
  END s_axi_wdata_4
  PIN s_axi_wdata_5
    DIRECTION INPUT ;
    USE SIGNAL ;
    ANTENNAGATEAREA 0.647700 ;
    ANTENNADIFFAREA 0.434700 ;
    PORT
      LAYER met2 ;
        RECT 101.290 298.510 101.570 298.790 ;
    END
  END s_axi_wdata_5
  PIN s_axi_wdata_6
    DIRECTION INPUT ;
    USE SIGNAL ;
    ANTENNAGATEAREA 0.647700 ;
    ANTENNADIFFAREA 0.434700 ;
    PORT
      LAYER met2 ;
        RECT 146.370 298.510 146.650 298.790 ;
    END
  END s_axi_wdata_6
  PIN s_axi_wdata_7
    DIRECTION INPUT ;
    USE SIGNAL ;
    ANTENNAGATEAREA 0.647700 ;
    ANTENNADIFFAREA 0.434700 ;
    PORT
      LAYER met2 ;
        RECT 138.090 298.510 138.370 298.790 ;
    END
  END s_axi_wdata_7
  PIN s_axi_wdata_8
    DIRECTION INPUT ;
    USE SIGNAL ;
    PORT
      LAYER met2 ;
        RECT 54.370 0.000 54.650 0.280 ;
    END
  END s_axi_wdata_8
  PIN s_axi_wdata_9
    DIRECTION INPUT ;
    USE SIGNAL ;
    PORT
      LAYER met2 ;
        RECT 55.290 0.000 55.570 0.280 ;
    END
  END s_axi_wdata_9
  PIN s_axi_wready
    DIRECTION OUTPUT ;
    USE SIGNAL ;
    ANTENNAGATEAREA 0.434700 ;
    ANTENNADIFFAREA 1.137600 ;
    PORT
      LAYER met2 ;
        RECT 176.730 298.510 177.010 298.790 ;
    END
  END s_axi_wready
  PIN s_axi_wstrb_0
    DIRECTION INPUT ;
    USE SIGNAL ;
    ANTENNAGATEAREA 0.647700 ;
    ANTENNADIFFAREA 0.434700 ;
    PORT
      LAYER met2 ;
        RECT 156.490 298.510 156.770 298.790 ;
    END
  END s_axi_wstrb_0
  PIN s_axi_wstrb_1
    DIRECTION INPUT ;
    USE SIGNAL ;
    PORT
      LAYER met2 ;
        RECT 56.210 0.000 56.490 0.280 ;
    END
  END s_axi_wstrb_1
  PIN s_axi_wstrb_2
    DIRECTION INPUT ;
    USE SIGNAL ;
    PORT
      LAYER met2 ;
        RECT 57.130 0.000 57.410 0.280 ;
    END
  END s_axi_wstrb_2
  PIN s_axi_wstrb_3
    DIRECTION INPUT ;
    USE SIGNAL ;
    PORT
      LAYER met2 ;
        RECT 58.050 0.000 58.330 0.280 ;
    END
  END s_axi_wstrb_3
  PIN s_axi_wvalid
    DIRECTION INPUT ;
    USE SIGNAL ;
    ANTENNAGATEAREA 0.647700 ;
    ANTENNADIFFAREA 0.434700 ;
    PORT
      LAYER met2 ;
        RECT 167.530 298.510 167.810 298.790 ;
    END
  END s_axi_wvalid
  PIN sleep_mode
    DIRECTION INPUT ;
    USE SIGNAL ;
    PORT
      LAYER met2 ;
        RECT 58.970 0.000 59.250 0.280 ;
    END
  END sleep_mode
  OBS
      LAYER nwell ;
        RECT 5.330 10.795 282.630 285.790 ;
      LAYER li1 ;
        RECT 5.520 10.795 282.440 285.685 ;
      LAYER met1 ;
        RECT 5.520 10.640 282.740 296.100 ;
      LAYER met2 ;
        RECT 5.610 298.230 11.770 298.510 ;
        RECT 12.610 298.230 34.770 298.510 ;
        RECT 35.610 298.230 35.690 298.510 ;
        RECT 36.530 298.230 99.170 298.510 ;
        RECT 100.010 298.230 100.090 298.510 ;
        RECT 100.930 298.230 101.010 298.510 ;
        RECT 101.850 298.230 127.690 298.510 ;
        RECT 128.530 298.230 128.610 298.510 ;
        RECT 129.450 298.230 129.530 298.510 ;
        RECT 130.370 298.230 131.370 298.510 ;
        RECT 132.210 298.230 137.810 298.510 ;
        RECT 138.650 298.230 138.730 298.510 ;
        RECT 139.570 298.230 143.330 298.510 ;
        RECT 144.170 298.230 146.090 298.510 ;
        RECT 146.930 298.230 147.010 298.510 ;
        RECT 147.850 298.230 153.450 298.510 ;
        RECT 154.290 298.230 155.290 298.510 ;
        RECT 156.130 298.230 156.210 298.510 ;
        RECT 157.050 298.230 157.130 298.510 ;
        RECT 157.970 298.230 158.050 298.510 ;
        RECT 158.890 298.230 158.970 298.510 ;
        RECT 159.810 298.230 162.650 298.510 ;
        RECT 163.490 298.230 163.570 298.510 ;
        RECT 164.410 298.230 166.330 298.510 ;
        RECT 167.170 298.230 167.250 298.510 ;
        RECT 168.090 298.230 168.170 298.510 ;
        RECT 169.010 298.230 170.930 298.510 ;
        RECT 171.770 298.230 171.850 298.510 ;
        RECT 172.690 298.230 174.610 298.510 ;
        RECT 175.450 298.230 175.530 298.510 ;
        RECT 176.370 298.230 176.450 298.510 ;
        RECT 177.290 298.230 177.370 298.510 ;
        RECT 178.210 298.230 178.290 298.510 ;
        RECT 179.130 298.230 180.130 298.510 ;
        RECT 180.970 298.230 181.970 298.510 ;
        RECT 182.810 298.230 182.890 298.510 ;
        RECT 183.730 298.230 184.730 298.510 ;
        RECT 185.570 298.230 187.490 298.510 ;
        RECT 188.330 298.230 196.690 298.510 ;
        RECT 197.530 298.230 197.610 298.510 ;
        RECT 198.450 298.230 198.530 298.510 ;
        RECT 199.370 298.230 199.450 298.510 ;
        RECT 200.290 298.230 202.210 298.510 ;
        RECT 203.050 298.230 204.050 298.510 ;
        RECT 204.890 298.230 210.490 298.510 ;
        RECT 211.330 298.230 215.090 298.510 ;
        RECT 215.930 298.230 216.010 298.510 ;
        RECT 216.850 298.230 216.930 298.510 ;
        RECT 217.770 298.230 227.050 298.510 ;
        RECT 227.890 298.230 227.970 298.510 ;
        RECT 228.810 298.230 230.730 298.510 ;
        RECT 231.570 298.230 232.570 298.510 ;
        RECT 233.410 298.230 281.890 298.510 ;
        RECT 5.610 0.560 281.890 298.230 ;
        RECT 6.170 0.280 6.250 0.560 ;
        RECT 7.090 0.280 7.170 0.560 ;
        RECT 8.010 0.280 8.090 0.560 ;
        RECT 8.930 0.280 9.010 0.560 ;
        RECT 9.850 0.280 9.930 0.560 ;
        RECT 10.770 0.280 10.850 0.560 ;
        RECT 11.690 0.280 11.770 0.560 ;
        RECT 12.610 0.280 12.690 0.560 ;
        RECT 13.530 0.280 13.610 0.560 ;
        RECT 14.450 0.280 14.530 0.560 ;
        RECT 15.370 0.280 15.450 0.560 ;
        RECT 16.290 0.280 16.370 0.560 ;
        RECT 17.210 0.280 17.290 0.560 ;
        RECT 18.130 0.280 18.210 0.560 ;
        RECT 19.050 0.280 19.130 0.560 ;
        RECT 19.970 0.280 20.050 0.560 ;
        RECT 20.890 0.280 20.970 0.560 ;
        RECT 21.810 0.280 21.890 0.560 ;
        RECT 22.730 0.280 22.810 0.560 ;
        RECT 23.650 0.280 23.730 0.560 ;
        RECT 24.570 0.280 24.650 0.560 ;
        RECT 25.490 0.280 25.570 0.560 ;
        RECT 26.410 0.280 26.490 0.560 ;
        RECT 27.330 0.280 27.410 0.560 ;
        RECT 28.250 0.280 28.330 0.560 ;
        RECT 29.170 0.280 29.250 0.560 ;
        RECT 30.090 0.280 30.170 0.560 ;
        RECT 31.010 0.280 31.090 0.560 ;
        RECT 31.930 0.280 32.010 0.560 ;
        RECT 32.850 0.280 32.930 0.560 ;
        RECT 33.770 0.280 33.850 0.560 ;
        RECT 34.690 0.280 34.770 0.560 ;
        RECT 35.610 0.280 35.690 0.560 ;
        RECT 36.530 0.280 36.610 0.560 ;
        RECT 37.450 0.280 37.530 0.560 ;
        RECT 38.370 0.280 38.450 0.560 ;
        RECT 39.290 0.280 39.370 0.560 ;
        RECT 40.210 0.280 40.290 0.560 ;
        RECT 41.130 0.280 41.210 0.560 ;
        RECT 42.050 0.280 42.130 0.560 ;
        RECT 42.970 0.280 43.050 0.560 ;
        RECT 43.890 0.280 43.970 0.560 ;
        RECT 44.810 0.280 44.890 0.560 ;
        RECT 45.730 0.280 45.810 0.560 ;
        RECT 46.650 0.280 46.730 0.560 ;
        RECT 47.570 0.280 47.650 0.560 ;
        RECT 48.490 0.280 48.570 0.560 ;
        RECT 49.410 0.280 49.490 0.560 ;
        RECT 50.330 0.280 50.410 0.560 ;
        RECT 51.250 0.280 51.330 0.560 ;
        RECT 52.170 0.280 52.250 0.560 ;
        RECT 53.090 0.280 53.170 0.560 ;
        RECT 54.010 0.280 54.090 0.560 ;
        RECT 54.930 0.280 55.010 0.560 ;
        RECT 55.850 0.280 55.930 0.560 ;
        RECT 56.770 0.280 56.850 0.560 ;
        RECT 57.690 0.280 57.770 0.560 ;
        RECT 58.610 0.280 58.690 0.560 ;
        RECT 59.530 0.280 66.970 0.560 ;
        RECT 67.810 0.280 94.570 0.560 ;
        RECT 95.410 0.280 114.810 0.560 ;
        RECT 115.650 0.280 115.730 0.560 ;
        RECT 116.570 0.280 116.650 0.560 ;
        RECT 117.490 0.280 117.570 0.560 ;
        RECT 118.410 0.280 118.490 0.560 ;
        RECT 119.330 0.280 119.410 0.560 ;
        RECT 120.250 0.280 120.330 0.560 ;
        RECT 121.170 0.280 126.770 0.560 ;
        RECT 127.610 0.280 127.690 0.560 ;
        RECT 128.530 0.280 150.690 0.560 ;
        RECT 151.530 0.280 185.650 0.560 ;
        RECT 186.490 0.280 192.090 0.560 ;
        RECT 192.930 0.280 204.050 0.560 ;
        RECT 204.890 0.280 205.890 0.560 ;
        RECT 206.730 0.280 207.730 0.560 ;
        RECT 208.570 0.280 209.570 0.560 ;
        RECT 210.410 0.280 281.890 0.560 ;
      LAYER met3 ;
        RECT 0.600 285.280 287.470 285.765 ;
        RECT 0.600 279.840 287.070 285.280 ;
        RECT 1.000 278.440 287.070 279.840 ;
        RECT 0.600 273.000 287.070 278.440 ;
        RECT 0.600 183.280 287.470 273.000 ;
        RECT 1.000 177.800 287.470 183.280 ;
        RECT 0.600 175.120 287.470 177.800 ;
        RECT 1.000 173.760 287.470 175.120 ;
        RECT 1.000 173.720 287.070 173.760 ;
        RECT 0.600 172.360 287.070 173.720 ;
        RECT 0.600 147.920 287.470 172.360 ;
        RECT 0.600 146.520 287.070 147.920 ;
        RECT 0.600 145.200 287.470 146.520 ;
        RECT 0.600 143.800 287.070 145.200 ;
        RECT 0.600 138.400 287.470 143.800 ;
        RECT 0.600 137.040 287.070 138.400 ;
        RECT 1.000 137.000 287.070 137.040 ;
        RECT 1.000 131.560 287.470 137.000 ;
        RECT 0.600 127.520 287.470 131.560 ;
        RECT 0.600 126.120 287.070 127.520 ;
        RECT 0.600 120.720 287.470 126.120 ;
        RECT 0.600 119.320 287.070 120.720 ;
        RECT 0.600 17.360 287.470 119.320 ;
        RECT 0.600 15.960 287.070 17.360 ;
        RECT 0.600 10.715 287.470 15.960 ;
      LAYER met4 ;
        RECT 48.135 26.695 174.240 283.385 ;
        RECT 176.640 26.695 177.540 283.385 ;
        RECT 179.940 26.695 233.385 283.385 ;
  END
END perf_counters
END LIBRARY

